One B-rep face of a CAD part: STEP entity #13603.
In plain terms, the planar face has unit normal (-0.99, -0.139, 0).
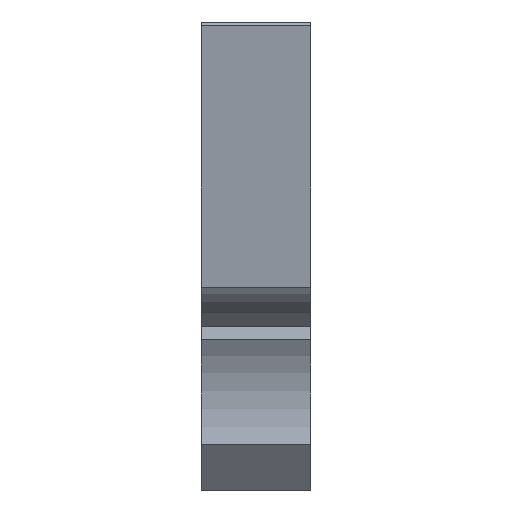
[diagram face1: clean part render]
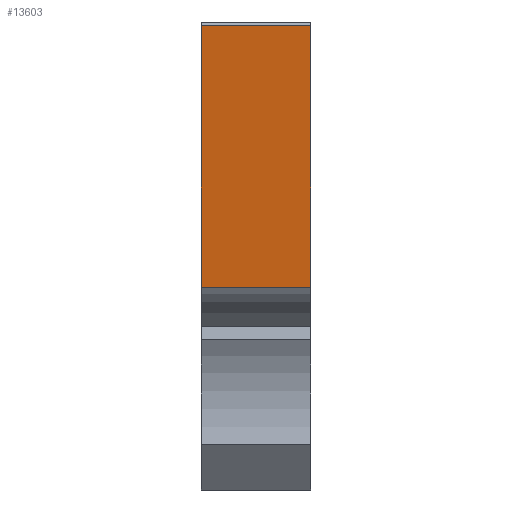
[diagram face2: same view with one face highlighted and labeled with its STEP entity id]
Its self-contained STEP definition (entity closure, numbers rounded to 3 decimals):
#8895 = PLANE('',#8896);
#8896 = AXIS2_PLACEMENT_3D('',#8897,#8898,#8899);
#8897 = CARTESIAN_POINT('',(0.,0.,0.));
#8898 = DIRECTION('',(0.,0.,1.));
#8899 = DIRECTION('',(1.,0.,0.));
#13398 = VERTEX_POINT('',#13399);
#13399 = CARTESIAN_POINT('',(-5.845,41.591,0.));
#13413 = PLANE('',#13414);
#13414 = AXIS2_PLACEMENT_3D('',#13415,#13416,#13417);
#13415 = CARTESIAN_POINT('',(-5.818,41.595,0.));
#13416 = DIRECTION('',(0.143,-0.99,0.));
#13417 = DIRECTION('',(-0.99,-0.143,0.));
#13425 = EDGE_CURVE('',#13426,#13398,#13428,.T.);
#13426 = VERTEX_POINT('',#13427);
#13427 = CARTESIAN_POINT('',(-1.809,12.873,0.));
#13428 = SURFACE_CURVE('',#13429,(#13433,#13439),.PCURVE_S1.);
#13429 = LINE('',#13430,#13431);
#13430 = CARTESIAN_POINT('',(-3.619,25.747,0.));
#13431 = VECTOR('',#13432,1.);
#13432 = DIRECTION('',(-0.139,0.99,0.));
#13433 = PCURVE('',#8895,#13434);
#13434 = DEFINITIONAL_REPRESENTATION('',(#13435),#13438);
#13435 = B_SPLINE_CURVE_WITH_KNOTS('',1,(#13436,#13437),.UNSPECIFIED.,
  .F.,.F.,(2,2),(-26.,16.413),.PIECEWISE_BEZIER_KNOTS.);
#13436 = CARTESIAN_POINT('',(0.,0.));
#13437 = CARTESIAN_POINT('',(-5.903,42.));
#13438 = ( GEOMETRIC_REPRESENTATION_CONTEXT(2) 
PARAMETRIC_REPRESENTATION_CONTEXT() REPRESENTATION_CONTEXT('2D SPACE',''
  ) );
#13439 = PCURVE('',#13440,#13445);
#13440 = PLANE('',#13441);
#13441 = AXIS2_PLACEMENT_3D('',#13442,#13443,#13444);
#13442 = CARTESIAN_POINT('',(-7.237,51.494,-1.));
#13443 = DIRECTION('',(0.99,0.139,-0.));
#13444 = DIRECTION('',(0.139,-0.99,0.));
#13445 = DEFINITIONAL_REPRESENTATION('',(#13446),#13449);
#13446 = B_SPLINE_CURVE_WITH_KNOTS('',1,(#13447,#13448),.UNSPECIFIED.,
  .F.,.F.,(2,2),(-26.,16.413),.PIECEWISE_BEZIER_KNOTS.);
#13447 = CARTESIAN_POINT('',(52.,-1.));
#13448 = CARTESIAN_POINT('',(9.587,-1.));
#13449 = ( GEOMETRIC_REPRESENTATION_CONTEXT(2) 
PARAMETRIC_REPRESENTATION_CONTEXT() REPRESENTATION_CONTEXT('2D SPACE',''
  ) );
#13470 = CYLINDRICAL_SURFACE('',#13471,13.);
#13471 = AXIS2_PLACEMENT_3D('',#13472,#13473,#13474);
#13472 = CARTESIAN_POINT('',(0.,0.,-1.));
#13473 = DIRECTION('',(-0.,-0.,-1.));
#13474 = DIRECTION('',(1.,0.,0.));
#13541 = PLANE('',#13542);
#13542 = AXIS2_PLACEMENT_3D('',#13543,#13544,#13545);
#13543 = CARTESIAN_POINT('',(0.,0.,12.)
  );
#13544 = DIRECTION('',(0.,0.,1.));
#13545 = DIRECTION('',(1.,0.,0.));
#13555 = EDGE_CURVE('',#13556,#13426,#13558,.T.);
#13556 = VERTEX_POINT('',#13557);
#13557 = CARTESIAN_POINT('',(-1.809,12.873,12.));
#13558 = SURFACE_CURVE('',#13559,(#13563,#13569),.PCURVE_S1.);
#13559 = LINE('',#13560,#13561);
#13560 = CARTESIAN_POINT('',(-1.809,12.873,-1.));
#13561 = VECTOR('',#13562,1.);
#13562 = DIRECTION('',(-0.,-0.,-1.));
#13563 = PCURVE('',#13470,#13564);
#13564 = DEFINITIONAL_REPRESENTATION('',(#13565),#13568);
#13565 = B_SPLINE_CURVE_WITH_KNOTS('',1,(#13566,#13567),.UNSPECIFIED.,
  .F.,.F.,(2,2),(-14.,0.),
  .PIECEWISE_BEZIER_KNOTS.);
#13566 = CARTESIAN_POINT('',(-1.71,-14.));
#13567 = CARTESIAN_POINT('',(-1.71,0.));
#13568 = ( GEOMETRIC_REPRESENTATION_CONTEXT(2) 
PARAMETRIC_REPRESENTATION_CONTEXT() REPRESENTATION_CONTEXT('2D SPACE',''
  ) );
#13569 = PCURVE('',#13440,#13570);
#13570 = DEFINITIONAL_REPRESENTATION('',(#13571),#13574);
#13571 = B_SPLINE_CURVE_WITH_KNOTS('',1,(#13572,#13573),.UNSPECIFIED.,
  .F.,.F.,(2,2),(-14.,0.),
  .PIECEWISE_BEZIER_KNOTS.);
#13572 = CARTESIAN_POINT('',(39.,-14.));
#13573 = CARTESIAN_POINT('',(39.,0.));
#13574 = ( GEOMETRIC_REPRESENTATION_CONTEXT(2) 
PARAMETRIC_REPRESENTATION_CONTEXT() REPRESENTATION_CONTEXT('2D SPACE',''
  ) );
#13603 = ADVANCED_FACE('',(#13604),#13440,.F.);
#13604 = FACE_BOUND('',#13605,.F.);
#13605 = EDGE_LOOP('',(#13606,#13607,#13608,#13629));
#13606 = ORIENTED_EDGE('',*,*,#13555,.T.);
#13607 = ORIENTED_EDGE('',*,*,#13425,.T.);
#13608 = ORIENTED_EDGE('',*,*,#13609,.T.);
#13609 = EDGE_CURVE('',#13398,#13610,#13612,.T.);
#13610 = VERTEX_POINT('',#13611);
#13611 = CARTESIAN_POINT('',(-5.845,41.591,12.));
#13612 = SURFACE_CURVE('',#13613,(#13617,#13623),.PCURVE_S1.);
#13613 = LINE('',#13614,#13615);
#13614 = CARTESIAN_POINT('',(-5.845,41.591,-0.5));
#13615 = VECTOR('',#13616,1.);
#13616 = DIRECTION('',(0.,0.,1.));
#13617 = PCURVE('',#13440,#13618);
#13618 = DEFINITIONAL_REPRESENTATION('',(#13619),#13622);
#13619 = B_SPLINE_CURVE_WITH_KNOTS('',1,(#13620,#13621),.UNSPECIFIED.,
  .F.,.F.,(2,2),(0.5,12.5),.PIECEWISE_BEZIER_KNOTS.);
#13620 = CARTESIAN_POINT('',(10.,-1.));
#13621 = CARTESIAN_POINT('',(10.,-13.));
#13622 = ( GEOMETRIC_REPRESENTATION_CONTEXT(2) 
PARAMETRIC_REPRESENTATION_CONTEXT() REPRESENTATION_CONTEXT('2D SPACE',''
  ) );
#13623 = PCURVE('',#13413,#13624);
#13624 = DEFINITIONAL_REPRESENTATION('',(#13625),#13628);
#13625 = B_SPLINE_CURVE_WITH_KNOTS('',1,(#13626,#13627),.UNSPECIFIED.,
  .F.,.F.,(2,2),(0.5,12.5),.PIECEWISE_BEZIER_KNOTS.);
#13626 = CARTESIAN_POINT('',(0.028,0.));
#13627 = CARTESIAN_POINT('',(0.028,-12.));
#13628 = ( GEOMETRIC_REPRESENTATION_CONTEXT(2) 
PARAMETRIC_REPRESENTATION_CONTEXT() REPRESENTATION_CONTEXT('2D SPACE',''
  ) );
#13629 = ORIENTED_EDGE('',*,*,#13630,.F.);
#13630 = EDGE_CURVE('',#13556,#13610,#13631,.T.);
#13631 = SURFACE_CURVE('',#13632,(#13636,#13642),.PCURVE_S1.);
#13632 = LINE('',#13633,#13634);
#13633 = CARTESIAN_POINT('',(-3.619,25.747,12.));
#13634 = VECTOR('',#13635,1.);
#13635 = DIRECTION('',(-0.139,0.99,0.));
#13636 = PCURVE('',#13440,#13637);
#13637 = DEFINITIONAL_REPRESENTATION('',(#13638),#13641);
#13638 = B_SPLINE_CURVE_WITH_KNOTS('',1,(#13639,#13640),.UNSPECIFIED.,
  .F.,.F.,(2,2),(-26.,16.413),.PIECEWISE_BEZIER_KNOTS.);
#13639 = CARTESIAN_POINT('',(52.,-13.));
#13640 = CARTESIAN_POINT('',(9.587,-13.));
#13641 = ( GEOMETRIC_REPRESENTATION_CONTEXT(2) 
PARAMETRIC_REPRESENTATION_CONTEXT() REPRESENTATION_CONTEXT('2D SPACE',''
  ) );
#13642 = PCURVE('',#13541,#13643);
#13643 = DEFINITIONAL_REPRESENTATION('',(#13644),#13647);
#13644 = B_SPLINE_CURVE_WITH_KNOTS('',1,(#13645,#13646),.UNSPECIFIED.,
  .F.,.F.,(2,2),(-26.,16.413),.PIECEWISE_BEZIER_KNOTS.);
#13645 = CARTESIAN_POINT('',(0.,0.));
#13646 = CARTESIAN_POINT('',(-5.903,42.));
#13647 = ( GEOMETRIC_REPRESENTATION_CONTEXT(2) 
PARAMETRIC_REPRESENTATION_CONTEXT() REPRESENTATION_CONTEXT('2D SPACE',''
  ) );
